VERSION 5.7 ;
  NOWIREEXTENSIONATPIN ON ;
  DIVIDERCHAR "/" ;
  BUSBITCHARS "[]" ;
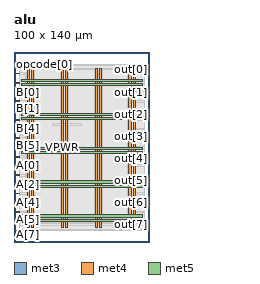
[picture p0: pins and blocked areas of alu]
MACRO alu
  CLASS BLOCK ;
  FOREIGN alu ;
  ORIGIN 0.000 0.000 ;
  SIZE 100.000 BY 140.000 ;
  PIN A[0]
    DIRECTION INPUT ;
    USE SIGNAL ;
    ANTENNAGATEAREA 0.196500 ;
    PORT
      LAYER met3 ;
        RECT 0.000 55.800 4.000 56.400 ;
    END
  END A[0]
  PIN A[1]
    DIRECTION INPUT ;
    USE SIGNAL ;
    ANTENNAGATEAREA 0.159000 ;
    PORT
      LAYER met3 ;
        RECT 0.000 49.000 4.000 49.600 ;
    END
  END A[1]
  PIN A[2]
    DIRECTION INPUT ;
    USE SIGNAL ;
    ANTENNAGATEAREA 0.213000 ;
    PORT
      LAYER met3 ;
        RECT 0.000 42.200 4.000 42.800 ;
    END
  END A[2]
  PIN A[3]
    DIRECTION INPUT ;
    USE SIGNAL ;
    ANTENNAGATEAREA 0.213000 ;
    PORT
      LAYER met3 ;
        RECT 0.000 35.400 4.000 36.000 ;
    END
  END A[3]
  PIN A[4]
    DIRECTION INPUT ;
    USE SIGNAL ;
    ANTENNAGATEAREA 0.213000 ;
    PORT
      LAYER met3 ;
        RECT 0.000 28.600 4.000 29.200 ;
    END
  END A[4]
  PIN A[5]
    DIRECTION INPUT ;
    USE SIGNAL ;
    ANTENNAGATEAREA 0.159000 ;
    PORT
      LAYER met3 ;
        RECT 0.000 21.800 4.000 22.400 ;
    END
  END A[5]
  PIN A[6]
    DIRECTION INPUT ;
    USE SIGNAL ;
    ANTENNAGATEAREA 0.213000 ;
    PORT
      LAYER met3 ;
        RECT 0.000 15.000 4.000 15.600 ;
    END
  END A[6]
  PIN A[7]
    DIRECTION INPUT ;
    USE SIGNAL ;
    ANTENNAGATEAREA 0.159000 ;
    PORT
      LAYER met3 ;
        RECT 0.000 8.200 4.000 8.800 ;
    END
  END A[7]
  PIN B[0]
    DIRECTION INPUT ;
    USE SIGNAL ;
    ANTENNAGATEAREA 0.213000 ;
    PORT
      LAYER met3 ;
        RECT 0.000 110.200 4.000 110.800 ;
    END
  END B[0]
  PIN B[1]
    DIRECTION INPUT ;
    USE SIGNAL ;
    ANTENNAGATEAREA 0.213000 ;
    PORT
      LAYER met3 ;
        RECT 0.000 103.400 4.000 104.000 ;
    END
  END B[1]
  PIN B[2]
    DIRECTION INPUT ;
    USE SIGNAL ;
    ANTENNAGATEAREA 0.159000 ;
    PORT
      LAYER met3 ;
        RECT 0.000 96.600 4.000 97.200 ;
    END
  END B[2]
  PIN B[3]
    DIRECTION INPUT ;
    USE SIGNAL ;
    ANTENNAGATEAREA 0.213000 ;
    PORT
      LAYER met3 ;
        RECT 0.000 89.800 4.000 90.400 ;
    END
  END B[3]
  PIN B[4]
    DIRECTION INPUT ;
    USE SIGNAL ;
    ANTENNAGATEAREA 0.159000 ;
    PORT
      LAYER met3 ;
        RECT 0.000 83.000 4.000 83.600 ;
    END
  END B[4]
  PIN B[5]
    DIRECTION INPUT ;
    USE SIGNAL ;
    ANTENNAGATEAREA 0.159000 ;
    PORT
      LAYER met3 ;
        RECT 0.000 76.200 4.000 76.800 ;
    END
  END B[5]
  PIN B[6]
    DIRECTION INPUT ;
    USE SIGNAL ;
    ANTENNAGATEAREA 0.159000 ;
    PORT
      LAYER met3 ;
        RECT 0.000 69.400 4.000 70.000 ;
    END
  END B[6]
  PIN B[7]
    DIRECTION INPUT ;
    USE SIGNAL ;
    ANTENNAGATEAREA 0.213000 ;
    PORT
      LAYER met3 ;
        RECT 0.000 62.600 4.000 63.200 ;
    END
  END B[7]
  PIN VGND
    DIRECTION INOUT ;
    USE GROUND ;
    PORT
      LAYER met4 ;
        RECT 13.020 10.640 14.620 128.080 ;
    END
    PORT
      LAYER met4 ;
        RECT 38.020 10.640 39.620 128.080 ;
    END
    PORT
      LAYER met4 ;
        RECT 63.020 10.640 64.620 128.080 ;
    END
    PORT
      LAYER met4 ;
        RECT 88.020 10.640 89.620 128.080 ;
    END
    PORT
      LAYER met5 ;
        RECT 5.280 18.380 94.540 19.980 ;
    END
    PORT
      LAYER met5 ;
        RECT 5.280 43.380 94.540 44.980 ;
    END
    PORT
      LAYER met5 ;
        RECT 5.280 68.380 94.540 69.980 ;
    END
    PORT
      LAYER met5 ;
        RECT 5.280 93.380 94.540 94.980 ;
    END
    PORT
      LAYER met5 ;
        RECT 5.280 118.380 94.540 119.980 ;
    END
  END VGND
  PIN VPWR
    DIRECTION INOUT ;
    USE POWER ;
    PORT
      LAYER met4 ;
        RECT 9.720 10.640 11.320 128.080 ;
    END
    PORT
      LAYER met4 ;
        RECT 34.720 10.640 36.320 128.080 ;
    END
    PORT
      LAYER met4 ;
        RECT 59.720 10.640 61.320 128.080 ;
    END
    PORT
      LAYER met4 ;
        RECT 84.720 10.640 86.320 128.080 ;
    END
    PORT
      LAYER met5 ;
        RECT 5.280 15.080 94.540 16.680 ;
    END
    PORT
      LAYER met5 ;
        RECT 5.280 40.080 94.540 41.680 ;
    END
    PORT
      LAYER met5 ;
        RECT 5.280 65.080 94.540 66.680 ;
    END
    PORT
      LAYER met5 ;
        RECT 5.280 90.080 94.540 91.680 ;
    END
    PORT
      LAYER met5 ;
        RECT 5.280 115.080 94.540 116.680 ;
    END
  END VPWR
  PIN opcode[0]
    DIRECTION INPUT ;
    USE SIGNAL ;
    ANTENNAGATEAREA 0.159000 ;
    PORT
      LAYER met3 ;
        RECT 0.000 130.600 4.000 131.200 ;
    END
  END opcode[0]
  PIN opcode[1]
    DIRECTION INPUT ;
    USE SIGNAL ;
    ANTENNAGATEAREA 0.213000 ;
    PORT
      LAYER met3 ;
        RECT 0.000 123.800 4.000 124.400 ;
    END
  END opcode[1]
  PIN opcode[2]
    DIRECTION INPUT ;
    USE SIGNAL ;
    ANTENNAGATEAREA 0.213000 ;
    PORT
      LAYER met3 ;
        RECT 0.000 117.000 4.000 117.600 ;
    END
  END opcode[2]
  PIN out[0]
    DIRECTION OUTPUT ;
    USE SIGNAL ;
    ANTENNADIFFAREA 0.445500 ;
    PORT
      LAYER met3 ;
        RECT 96.000 126.520 100.000 127.120 ;
    END
  END out[0]
  PIN out[1]
    DIRECTION OUTPUT ;
    USE SIGNAL ;
    ANTENNADIFFAREA 0.445500 ;
    PORT
      LAYER met3 ;
        RECT 96.000 110.200 100.000 110.800 ;
    END
  END out[1]
  PIN out[2]
    DIRECTION OUTPUT ;
    USE SIGNAL ;
    ANTENNADIFFAREA 0.445500 ;
    PORT
      LAYER met3 ;
        RECT 96.000 93.880 100.000 94.480 ;
    END
  END out[2]
  PIN out[3]
    DIRECTION OUTPUT ;
    USE SIGNAL ;
    ANTENNADIFFAREA 0.445500 ;
    PORT
      LAYER met3 ;
        RECT 96.000 77.560 100.000 78.160 ;
    END
  END out[3]
  PIN out[4]
    DIRECTION OUTPUT ;
    USE SIGNAL ;
    ANTENNADIFFAREA 0.445500 ;
    PORT
      LAYER met3 ;
        RECT 96.000 61.240 100.000 61.840 ;
    END
  END out[4]
  PIN out[5]
    DIRECTION OUTPUT ;
    USE SIGNAL ;
    ANTENNADIFFAREA 0.445500 ;
    PORT
      LAYER met3 ;
        RECT 96.000 44.920 100.000 45.520 ;
    END
  END out[5]
  PIN out[6]
    DIRECTION OUTPUT ;
    USE SIGNAL ;
    ANTENNADIFFAREA 0.795200 ;
    PORT
      LAYER met3 ;
        RECT 96.000 28.600 100.000 29.200 ;
    END
  END out[6]
  PIN out[7]
    DIRECTION OUTPUT ;
    USE SIGNAL ;
    ANTENNADIFFAREA 0.445500 ;
    PORT
      LAYER met3 ;
        RECT 96.000 12.280 100.000 12.880 ;
    END
  END out[7]
  OBS
      LAYER nwell ;
        RECT 5.330 10.795 94.490 128.030 ;
      LAYER li1 ;
        RECT 5.520 10.795 94.300 127.925 ;
      LAYER met1 ;
        RECT 4.210 10.640 94.300 128.080 ;
      LAYER met2 ;
        RECT 4.230 8.995 93.290 130.405 ;
      LAYER met3 ;
        RECT 4.400 130.200 96.000 131.050 ;
        RECT 3.990 127.520 96.000 130.200 ;
        RECT 3.990 126.120 95.600 127.520 ;
        RECT 3.990 124.800 96.000 126.120 ;
        RECT 4.400 123.400 96.000 124.800 ;
        RECT 3.990 118.000 96.000 123.400 ;
        RECT 4.400 116.600 96.000 118.000 ;
        RECT 3.990 111.200 96.000 116.600 ;
        RECT 4.400 109.800 95.600 111.200 ;
        RECT 3.990 104.400 96.000 109.800 ;
        RECT 4.400 103.000 96.000 104.400 ;
        RECT 3.990 97.600 96.000 103.000 ;
        RECT 4.400 96.200 96.000 97.600 ;
        RECT 3.990 94.880 96.000 96.200 ;
        RECT 3.990 93.480 95.600 94.880 ;
        RECT 3.990 90.800 96.000 93.480 ;
        RECT 4.400 89.400 96.000 90.800 ;
        RECT 3.990 84.000 96.000 89.400 ;
        RECT 4.400 82.600 96.000 84.000 ;
        RECT 3.990 78.560 96.000 82.600 ;
        RECT 3.990 77.200 95.600 78.560 ;
        RECT 4.400 77.160 95.600 77.200 ;
        RECT 4.400 75.800 96.000 77.160 ;
        RECT 3.990 70.400 96.000 75.800 ;
        RECT 4.400 69.000 96.000 70.400 ;
        RECT 3.990 63.600 96.000 69.000 ;
        RECT 4.400 62.240 96.000 63.600 ;
        RECT 4.400 62.200 95.600 62.240 ;
        RECT 3.990 60.840 95.600 62.200 ;
        RECT 3.990 56.800 96.000 60.840 ;
        RECT 4.400 55.400 96.000 56.800 ;
        RECT 3.990 50.000 96.000 55.400 ;
        RECT 4.400 48.600 96.000 50.000 ;
        RECT 3.990 45.920 96.000 48.600 ;
        RECT 3.990 44.520 95.600 45.920 ;
        RECT 3.990 43.200 96.000 44.520 ;
        RECT 4.400 41.800 96.000 43.200 ;
        RECT 3.990 36.400 96.000 41.800 ;
        RECT 4.400 35.000 96.000 36.400 ;
        RECT 3.990 29.600 96.000 35.000 ;
        RECT 4.400 28.200 95.600 29.600 ;
        RECT 3.990 22.800 96.000 28.200 ;
        RECT 4.400 21.400 96.000 22.800 ;
        RECT 3.990 16.000 96.000 21.400 ;
        RECT 4.400 14.600 96.000 16.000 ;
        RECT 3.990 13.280 96.000 14.600 ;
        RECT 3.990 11.880 95.600 13.280 ;
        RECT 3.990 9.200 96.000 11.880 ;
        RECT 4.400 8.350 96.000 9.200 ;
      LAYER met4 ;
        RECT 8.575 17.175 9.320 126.985 ;
        RECT 11.720 17.175 12.620 126.985 ;
        RECT 15.020 17.175 34.320 126.985 ;
        RECT 36.720 17.175 37.620 126.985 ;
        RECT 40.020 17.175 59.320 126.985 ;
        RECT 61.720 17.175 62.620 126.985 ;
        RECT 65.020 17.175 83.425 126.985 ;
      LAYER met5 ;
        RECT 28.180 85.900 50.020 87.500 ;
  END
END alu
END LIBRARY

